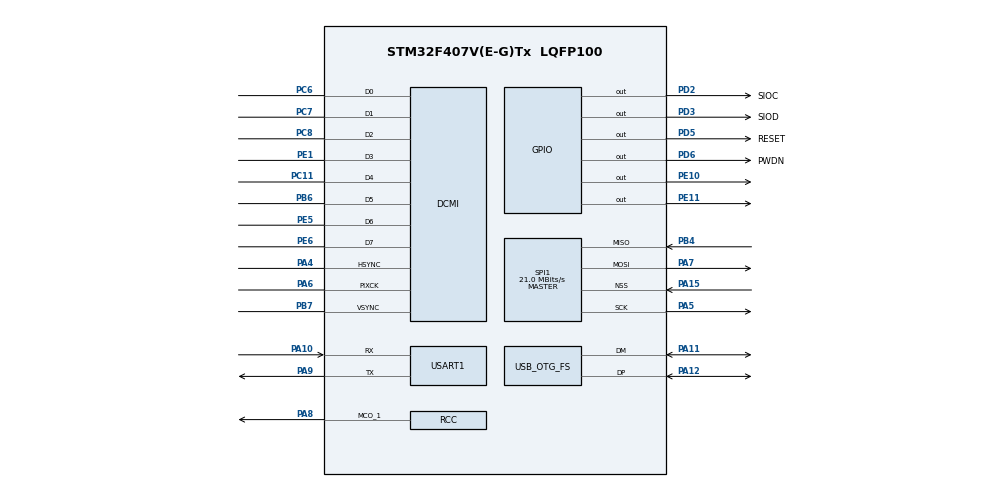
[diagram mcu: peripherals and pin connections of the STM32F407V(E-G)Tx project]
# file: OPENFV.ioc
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DCMI.JPEGMode=DCMI_JPEG_DISABLE
Dma.DCMI.0.Direction=DMA_PERIPH_TO_MEMORY
Dma.DCMI.0.FIFOMode=DMA_FIFOMODE_ENABLE
Dma.DCMI.0.FIFOThreshold=DMA_FIFO_THRESHOLD_HALFFULL
Dma.DCMI.0.Instance=DMA2_Stream1
Dma.DCMI.0.MemBurst=DMA_MBURST_SINGLE
Dma.DCMI.0.MemDataAlignment=DMA_MDATAALIGN_WORD
Dma.DCMI.0.MemInc=DMA_MINC_ENABLE
Dma.DCMI.0.Mode=DMA_CIRCULAR
Dma.DCMI.0.PeriphBurst=DMA_PBURST_SINGLE
Dma.DCMI.0.PeriphDataAlignment=DMA_PDATAALIGN_WORD
Dma.DCMI.0.PeriphInc=DMA_PINC_DISABLE
Dma.DCMI.0.Priority=DMA_PRIORITY_VERY_HIGH
Dma.Request0=DCMI
Mcu.Family=STM32F4
Mcu.Name=STM32F407V(E-G)Tx
Mcu.Package=LQFP100
NVIC.DMA2_Stream1_IRQn=true\:0\:0\:false\:false\:true\:false\:true
NVIC.OTG_FS_IRQn=true\:0\:0\:false\:false\:true\:false\:true
NVIC.PriorityGroup=NVIC_PRIORITYGROUP_4
PA10.Mode=Multiprocessor_communication
PA10.Signal=USART1_RX
PA11.Mode=Device_Only
PA11.Signal=USB_OTG_FS_DM
PA12.Mode=Device_Only
PA12.Signal=USB_OTG_FS_DP
PA15.Mode=NSS_Signal_Hard_Input
PA15.Signal=SPI1_NSS
PA4.Mode=Slave_8_bits_External_Synchro
PA4.Signal=DCMI_HSYNC
PA5.Mode=Full_Duplex_Master
PA5.Signal=SPI1_SCK
PA6.Mode=Slave_8_bits_External_Synchro
PA6.Signal=DCMI_PIXCK
PA7.Mode=Full_Duplex_Master
PA7.Signal=SPI1_MOSI
PA8.Mode=Clock-out-1
PA8.Signal=RCC_MCO_1
PA9.Mode=Multiprocessor_communication
PA9.Signal=USART1_TX
PB4.Mode=Full_Duplex_Master
PB4.Signal=SPI1_MISO
PB6.Mode=Slave_8_bits_External_Synchro
PB6.Signal=DCMI_D5
PB7.Mode=Slave_8_bits_External_Synchro
PB7.Signal=DCMI_VSYNC
PC11.Mode=Slave_8_bits_External_Synchro
PC11.Signal=DCMI_D4
PC14-OSC32_IN.Mode=LSE-External-Clock-Source
PC14-OSC32_IN.Signal=RCC_OSC32_IN
PC15-OSC32_OUT.Mode=LSE-External-Clock-Source
PC15-OSC32_OUT.Signal=RCC_OSC32_OUT
PC6.Mode=Slave_8_bits_External_Synchro
PC6.Signal=DCMI_D0
PC7.Mode=Slave_8_bits_External_Synchro
PC7.Signal=DCMI_D1
PC8.Mode=Slave_8_bits_External_Synchro
PC8.Signal=DCMI_D2
PD2.GPIO_Label=SIOC
PD2.Signal=GPIO_Output
PD3.GPIO_Label=SIOD
PD3.Signal=GPIO_Output
PD5.GPIO_Label=RESET
PD5.Signal=GPIO_Output
PD6.GPIO_Label=PWDN
PD6.Signal=GPIO_Output
PE1.Mode=Slave_8_bits_External_Synchro
PE1.Signal=DCMI_D3
PE10.Signal=GPIO_Output
PE11.Signal=GPIO_Output
PE5.Mode=Slave_8_bits_External_Synchro
PE5.Signal=DCMI_D6
PE6.Mode=Slave_8_bits_External_Synchro
PE6.Signal=DCMI_D7
PH0-OSC_IN.Mode=HSE-External-Oscillator
PH0-OSC_IN.Signal=RCC_OSC_IN
PH1-OSC_OUT.Mode=HSE-External-Oscillator
PH1-OSC_OUT.Signal=RCC_OSC_OUT
ProjectManager.HeapSize=0x200
ProjectManager.StackSize=0x400
ProjectManager.TargetToolchain=MDK-ARM V5
RCC.48MHZClocksFreq_Value=48000000
RCC.AHBFreq_Value=84000000
RCC.APB1CLKDivider=RCC_HCLK_DIV2
RCC.APB1Freq_Value=42000000
RCC.APB1TimFreq_Value=84000000
RCC.APB2CLKDivider=RCC_HCLK_DIV2
RCC.APB2Freq_Value=42000000
RCC.APB2TimFreq_Value=84000000
RCC.CortexFreq_Value=84000000
RCC.HCLKFreq_Value=84000000
RCC.HSE_VALUE=8000000
RCC.HSI_VALUE=16000000
RCC.LSE_VALUE=32768
RCC.PLLM=8
RCC.PLLN=336
RCC.PLLP=RCC_PLLP_DIV4
RCC.PLLQ=7
RCC.SYSCLKFreq_VALUE=84000000
RCC.SYSCLKSource=RCC_SYSCLKSOURCE_PLLCLK
RCC.VCOOutputFreq_Value=336000000
SPI1.BaudRatePrescaler=SPI_BAUDRATEPRESCALER_2
SPI1.CalculateBaudRate=21.0 MBits/s
SPI1.Direction=SPI_DIRECTION_2LINES
SPI1.Mode=SPI_MODE_MASTER
SPI1.VirtualNSS=VM_NSSHARD
SPI1.VirtualType=VM_MASTER
USART1.VirtualMode=VM_ASYNC
USB_DEVICE.CLASS_NAME_FS=CDC
USB_DEVICE.VirtualMode-CDC_FS=Cdc
USB_DEVICE.VirtualModeFS=Cdc_FS
USB_OTG_FS.VirtualMode=Device_Only
VP_USB_DEVICE_VS_USB_DEVICE_CDC_FS.Mode=CDC_FS
board=custom

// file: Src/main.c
/* USER CODE BEGIN Header */
/**
  ******************************************************************************
  * @file           : main.c
  * @brief          : Main program body
  ******************************************************************************
  ** This notice applies to any and all portions of this file
  * that are not between comment pairs USER CODE BEGIN and
  * USER CODE END. Other portions of this file, whether
  * inserted by the user or by software development tools
  * are owned by their respective copyright owners.
  *
  * COPYRIGHT(c) 2019 STMicroelectronics
  *
  * Redistribution and use in source and binary forms, with or without modification,
  * are permitted provided that the following conditions are met:
  *   1. Redistributions of source code must retain the above copyright notice,
  *      this list of conditions and the following disclaimer.
  *   2. Redistributions in binary form must reproduce the above copyright notice,
  *      this list of conditions and the following disclaimer in the documentation
  *      and/or other materials provided with the distribution.
  *   3. Neither the name of STMicroelectronics nor the names of its contributors
  *      may be used to endorse or promote products derived from this software
  *      without specific prior written permission.
  *
  * THIS SOFTWARE IS PROVIDED BY THE COPYRIGHT HOLDERS AND CONTRIBUTORS "AS IS"
  * AND ANY EXPRESS OR IMPLIED WARRANTIES, INCLUDING, BUT NOT LIMITED TO, THE
  * IMPLIED WARRANTIES OF MERCHANTABILITY AND FITNESS FOR A PARTICULAR PURPOSE ARE
  * DISCLAIMED. IN NO EVENT SHALL THE COPYRIGHT HOLDER OR CONTRIBUTORS BE LIABLE
  * FOR ANY DIRECT, INDIRECT, INCIDENTAL, SPECIAL, EXEMPLARY, OR CONSEQUENTIAL
  * DAMAGES (INCLUDING, BUT NOT LIMITED TO, PROCUREMENT OF SUBSTITUTE GOODS OR
  * SERVICES; LOSS OF USE, DATA, OR PROFITS; OR BUSINESS INTERRUPTION) HOWEVER
  * CAUSED AND ON ANY THEORY OF LIABILITY, WHETHER IN CONTRACT, STRICT LIABILITY,
  * OR TORT (INCLUDING NEGLIGENCE OR OTHERWISE) ARISING IN ANY WAY OUT OF THE USE
  * OF THIS SOFTWARE, EVEN IF ADVISED OF THE POSSIBILITY OF SUCH DAMAGE.
  *
  ******************************************************************************
  */
/* USER CODE END Header */

#include "main.h"
#include "usb_device.h"

DCMI_HandleTypeDef hdcmi;
DMA_HandleTypeDef hdma_dcmi;

SPI_HandleTypeDef hspi1;

UART_HandleTypeDef huart1;

void SystemClock_Config(void);
static void MX_GPIO_Init(void);
static void MX_DMA_Init(void);
static void MX_DCMI_Init(void);
static void MX_SPI1_Init(void);
static void MX_USART1_UART_Init(void);

int main(void)
{

  /* MCU Configuration--------------------------------------------------------*/

  /* Reset of all peripherals, Initializes the Flash interface and the Systick. */
  HAL_Init();

  /* Configure the system clock */
  SystemClock_Config();

  /* Initialize all configured peripherals */
  MX_GPIO_Init();
  MX_DMA_Init();
  MX_DCMI_Init();
  MX_SPI1_Init();
  MX_USART1_UART_Init();
  MX_USB_DEVICE_Init();
  /* USER CODE BEGIN 2 */
    delay_init(168);
  /* USER CODE END 2 */

  /* Infinite loop */
  while (1)
  {
        led_blue_toggle();
        delay_ms(500);
  }
}

void SystemClock_Config(void)
{
  RCC_OscInitTypeDef RCC_OscInitStruct = {0};
  RCC_ClkInitTypeDef RCC_ClkInitStruct = {0};

  /**Configure the main internal regulator output voltage
  */
  __HAL_RCC_PWR_CLK_ENABLE();
  __HAL_PWR_VOLTAGESCALING_CONFIG(PWR_REGULATOR_VOLTAGE_SCALE1);
  /**Initializes the CPU, AHB and APB busses clocks
  */
  RCC_OscInitStruct.OscillatorType = RCC_OSCILLATORTYPE_HSE;
  RCC_OscInitStruct.HSEState = RCC_HSE_ON;
//  RCC_OscInitStruct.HSIState = RCC_HSI_OFF;
//  RCC_OscInitStruct.HSICalibrationValue = RCC_HSICALIBRATION_DEFAULT;
  RCC_OscInitStruct.PLL.PLLState = RCC_PLL_ON;
  RCC_OscInitStruct.PLL.PLLSource = RCC_PLLSOURCE_HSE;
  RCC_OscInitStruct.PLL.PLLM = 8;
  RCC_OscInitStruct.PLL.PLLN = 336;
  RCC_OscInitStruct.PLL.PLLP = RCC_PLLP_DIV2;
  RCC_OscInitStruct.PLL.PLLQ = 7;
  if (HAL_RCC_OscConfig(&RCC_OscInitStruct) != HAL_OK)
  {
    Error_Handler();
  }
  /**Initializes the CPU, AHB and APB busses clocks
  */
  RCC_ClkInitStruct.ClockType = RCC_CLOCKTYPE_HCLK|RCC_CLOCKTYPE_SYSCLK
                              |RCC_CLOCKTYPE_PCLK1|RCC_CLOCKTYPE_PCLK2;
  RCC_ClkInitStruct.SYSCLKSource = RCC_SYSCLKSOURCE_PLLCLK;
  RCC_ClkInitStruct.AHBCLKDivider = RCC_SYSCLK_DIV1;
  RCC_ClkInitStruct.APB1CLKDivider = RCC_HCLK_DIV4;
  RCC_ClkInitStruct.APB2CLKDivider = RCC_HCLK_DIV2;

  if (HAL_RCC_ClockConfig(&RCC_ClkInitStruct, FLASH_LATENCY_5) != HAL_OK)
  {
    Error_Handler();
  }
  HAL_RCC_MCOConfig(RCC_MCO1, RCC_MCO1SOURCE_HSI, RCC_MCODIV_1);
}

static void MX_DCMI_Init(void)
{

  hdcmi.Instance = DCMI;
  hdcmi.Init.SynchroMode = DCMI_SYNCHRO_HARDWARE;
  hdcmi.Init.PCKPolarity = DCMI_PCKPOLARITY_FALLING;
  hdcmi.Init.VSPolarity = DCMI_VSPOLARITY_LOW;
  hdcmi.Init.HSPolarity = DCMI_HSPOLARITY_LOW;
  hdcmi.Init.CaptureRate = DCMI_CR_ALL_FRAME;
  hdcmi.Init.ExtendedDataMode = DCMI_EXTEND_DATA_8B;
  hdcmi.Init.JPEGMode = DCMI_JPEG_DISABLE;
  if (HAL_DCMI_Init(&hdcmi) != HAL_OK)
  {
    Error_Handler();
  }

}

static void MX_SPI1_Init(void)
{

  /* SPI1 parameter configuration*/
  hspi1.Instance = SPI1;
  hspi1.Init.Mode = SPI_MODE_MASTER;
  hspi1.Init.Direction = SPI_DIRECTION_2LINES;
  hspi1.Init.DataSize = SPI_DATASIZE_8BIT;
  hspi1.Init.CLKPolarity = SPI_POLARITY_LOW;
  hspi1.Init.CLKPhase = SPI_PHASE_1EDGE;
  hspi1.Init.NSS = SPI_NSS_HARD_INPUT;
  hspi1.Init.BaudRatePrescaler = SPI_BAUDRATEPRESCALER_2;
  hspi1.Init.FirstBit = SPI_FIRSTBIT_MSB;
  hspi1.Init.TIMode = SPI_TIMODE_DISABLE;
  hspi1.Init.CRCCalculation = SPI_CRCCALCULATION_DISABLE;
  hspi1.Init.CRCPolynomial = 10;
  if (HAL_SPI_Init(&hspi1) != HAL_OK)
  {
    Error_Handler();
  }

}

static void MX_USART1_UART_Init(void)
{

  huart1.Instance = USART1;
  huart1.Init.BaudRate = 115200;
  huart1.Init.WordLength = UART_WORDLENGTH_8B;
  huart1.Init.StopBits = UART_STOPBITS_1;
  huart1.Init.Parity = UART_PARITY_NONE;
  huart1.Init.Mode = UART_MODE_TX_RX;
  huart1.Init.HwFlowCtl = UART_HWCONTROL_NONE;
  huart1.Init.OverSampling = UART_OVERSAMPLING_16;
  if (HAL_MultiProcessor_Init(&huart1, 0, UART_WAKEUPMETHOD_IDLELINE) != HAL_OK)
  {
    Error_Handler();
  }

}

static void MX_DMA_Init(void)
{
  /* DMA controller clock enable */
  __HAL_RCC_DMA2_CLK_ENABLE();

  /* DMA interrupt init */
  /* DMA2_Stream1_IRQn interrupt configuration */
  HAL_NVIC_SetPriority(DMA2_Stream1_IRQn, 0, 0);
  HAL_NVIC_EnableIRQ(DMA2_Stream1_IRQn);

}

static void MX_GPIO_Init(void)
{
  LL_GPIO_InitTypeDef GPIO_InitStruct = {0};

  /* GPIO Ports Clock Enable */
  LL_AHB1_GRP1_EnableClock(LL_AHB1_GRP1_PERIPH_GPIOE);
  LL_AHB1_GRP1_EnableClock(LL_AHB1_GRP1_PERIPH_GPIOC);
  LL_AHB1_GRP1_EnableClock(LL_AHB1_GRP1_PERIPH_GPIOH);
  LL_AHB1_GRP1_EnableClock(LL_AHB1_GRP1_PERIPH_GPIOA);
  LL_AHB1_GRP1_EnableClock(LL_AHB1_GRP1_PERIPH_GPIOB);

  /**/
  LL_GPIO_ResetOutputPin(GPIOE, LL_GPIO_PIN_10|LL_GPIO_PIN_11);

  /**/
  GPIO_InitStruct.Pin = LL_GPIO_PIN_10|LL_GPIO_PIN_11;
  GPIO_InitStruct.Mode = LL_GPIO_MODE_OUTPUT;
  GPIO_InitStruct.Speed = LL_GPIO_SPEED_FREQ_LOW;
  GPIO_InitStruct.OutputType = LL_GPIO_OUTPUT_PUSHPULL;
  GPIO_InitStruct.Pull = LL_GPIO_PULL_NO;
  LL_GPIO_Init(GPIOE, &GPIO_InitStruct);

  /**/
  GPIO_InitStruct.Pin = LL_GPIO_PIN_8;
  GPIO_InitStruct.Mode = LL_GPIO_MODE_ALTERNATE;
  GPIO_InitStruct.Speed = LL_GPIO_SPEED_FREQ_LOW;
  GPIO_InitStruct.OutputType = LL_GPIO_OUTPUT_PUSHPULL;
  GPIO_InitStruct.Pull = LL_GPIO_PULL_NO;
  GPIO_InitStruct.Alternate = LL_GPIO_AF_0;
  LL_GPIO_Init(GPIOA, &GPIO_InitStruct);

}

void Error_Handler(void)
{
}

/************************ (C) COPYRIGHT STMicroelectronics *****END OF FILE****/
